VERSION 5.7 ;
BUSBITCHARS "[]" ;
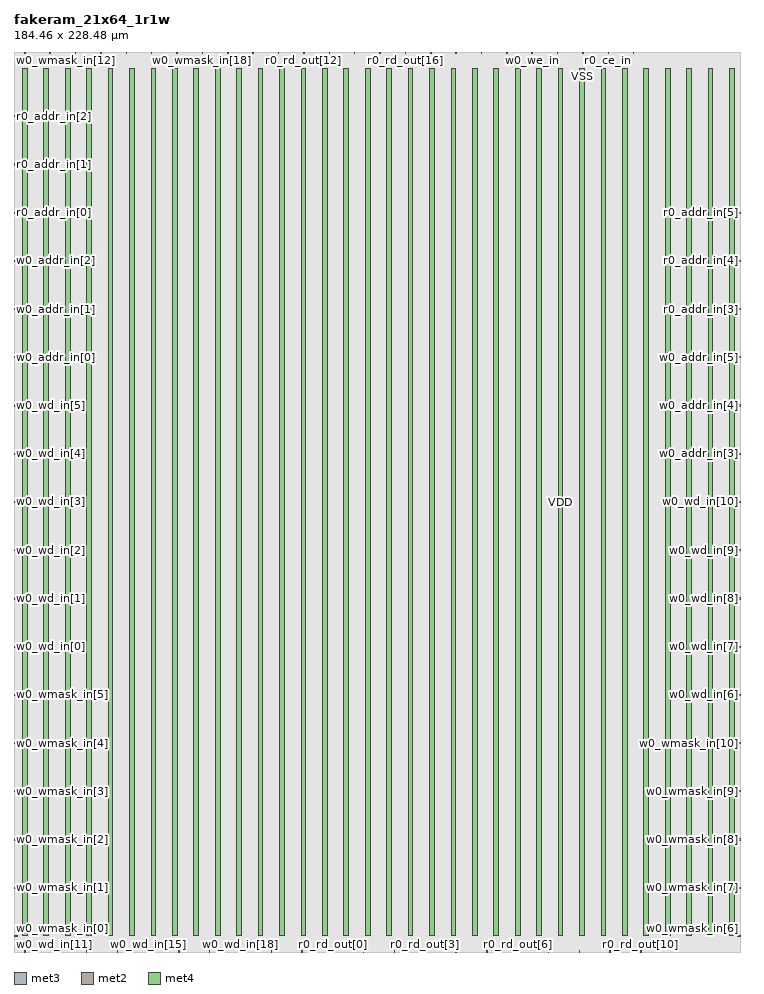
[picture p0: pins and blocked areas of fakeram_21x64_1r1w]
MACRO fakeram_21x64_1r1w
  FOREIGN fakeram_21x64_1r1w 0 0 ;
  SYMMETRY X Y R90 ;
  SIZE 184.460 BY 228.480 ;
  CLASS BLOCK ;
  PIN w0_wmask_in[0]
    DIRECTION INPUT ;
    USE SIGNAL ;
    SHAPE ABUTMENT ;
    PORT
      LAYER met3 ;
      RECT 0.000 3.930 0.900 4.230 ;
    END
  END w0_wmask_in[0]
  PIN w0_wmask_in[1]
    DIRECTION INPUT ;
    USE SIGNAL ;
    SHAPE ABUTMENT ;
    PORT
      LAYER met3 ;
      RECT 0.000 16.170 0.900 16.470 ;
    END
  END w0_wmask_in[1]
  PIN w0_wmask_in[2]
    DIRECTION INPUT ;
    USE SIGNAL ;
    SHAPE ABUTMENT ;
    PORT
      LAYER met3 ;
      RECT 0.000 28.410 0.900 28.710 ;
    END
  END w0_wmask_in[2]
  PIN w0_wmask_in[3]
    DIRECTION INPUT ;
    USE SIGNAL ;
    SHAPE ABUTMENT ;
    PORT
      LAYER met3 ;
      RECT 0.000 40.650 0.900 40.950 ;
    END
  END w0_wmask_in[3]
  PIN w0_wmask_in[4]
    DIRECTION INPUT ;
    USE SIGNAL ;
    SHAPE ABUTMENT ;
    PORT
      LAYER met3 ;
      RECT 0.000 52.890 0.900 53.190 ;
    END
  END w0_wmask_in[4]
  PIN w0_wmask_in[5]
    DIRECTION INPUT ;
    USE SIGNAL ;
    SHAPE ABUTMENT ;
    PORT
      LAYER met3 ;
      RECT 0.000 65.130 0.900 65.430 ;
    END
  END w0_wmask_in[5]
  PIN w0_wmask_in[6]
    DIRECTION INPUT ;
    USE SIGNAL ;
    SHAPE ABUTMENT ;
    PORT
      LAYER met3 ;
      RECT 183.560 3.930 184.460 4.230 ;
    END
  END w0_wmask_in[6]
  PIN w0_wmask_in[7]
    DIRECTION INPUT ;
    USE SIGNAL ;
    SHAPE ABUTMENT ;
    PORT
      LAYER met3 ;
      RECT 183.560 16.170 184.460 16.470 ;
    END
  END w0_wmask_in[7]
  PIN w0_wmask_in[8]
    DIRECTION INPUT ;
    USE SIGNAL ;
    SHAPE ABUTMENT ;
    PORT
      LAYER met3 ;
      RECT 183.560 28.410 184.460 28.710 ;
    END
  END w0_wmask_in[8]
  PIN w0_wmask_in[9]
    DIRECTION INPUT ;
    USE SIGNAL ;
    SHAPE ABUTMENT ;
    PORT
      LAYER met3 ;
      RECT 183.560 40.650 184.460 40.950 ;
    END
  END w0_wmask_in[9]
  PIN w0_wmask_in[10]
    DIRECTION INPUT ;
    USE SIGNAL ;
    SHAPE ABUTMENT ;
    PORT
      LAYER met3 ;
      RECT 183.560 52.890 184.460 53.190 ;
    END
  END w0_wmask_in[10]
  PIN w0_wmask_in[11]
    DIRECTION INPUT ;
    USE SIGNAL ;
    SHAPE ABUTMENT ;
    PORT
      LAYER met2 ;
      RECT 2.690 228.060 2.830 228.480 ;
    END
  END w0_wmask_in[11]
  PIN w0_wmask_in[12]
    DIRECTION INPUT ;
    USE SIGNAL ;
    SHAPE ABUTMENT ;
    PORT
      LAYER met2 ;
      RECT 9.130 228.060 9.270 228.480 ;
    END
  END w0_wmask_in[12]
  PIN w0_wmask_in[13]
    DIRECTION INPUT ;
    USE SIGNAL ;
    SHAPE ABUTMENT ;
    PORT
      LAYER met2 ;
      RECT 15.570 228.060 15.710 228.480 ;
    END
  END w0_wmask_in[13]
  PIN w0_wmask_in[14]
    DIRECTION INPUT ;
    USE SIGNAL ;
    SHAPE ABUTMENT ;
    PORT
      LAYER met2 ;
      RECT 22.010 228.060 22.150 228.480 ;
    END
  END w0_wmask_in[14]
  PIN w0_wmask_in[15]
    DIRECTION INPUT ;
    USE SIGNAL ;
    SHAPE ABUTMENT ;
    PORT
      LAYER met2 ;
      RECT 28.450 228.060 28.590 228.480 ;
    END
  END w0_wmask_in[15]
  PIN w0_wmask_in[16]
    DIRECTION INPUT ;
    USE SIGNAL ;
    SHAPE ABUTMENT ;
    PORT
      LAYER met2 ;
      RECT 34.890 228.060 35.030 228.480 ;
    END
  END w0_wmask_in[16]
  PIN w0_wmask_in[17]
    DIRECTION INPUT ;
    USE SIGNAL ;
    SHAPE ABUTMENT ;
    PORT
      LAYER met2 ;
      RECT 41.330 228.060 41.470 228.480 ;
    END
  END w0_wmask_in[17]
  PIN w0_wmask_in[18]
    DIRECTION INPUT ;
    USE SIGNAL ;
    SHAPE ABUTMENT ;
    PORT
      LAYER met2 ;
      RECT 47.770 228.060 47.910 228.480 ;
    END
  END w0_wmask_in[18]
  PIN w0_wmask_in[19]
    DIRECTION INPUT ;
    USE SIGNAL ;
    SHAPE ABUTMENT ;
    PORT
      LAYER met2 ;
      RECT 54.210 228.060 54.350 228.480 ;
    END
  END w0_wmask_in[19]
  PIN w0_wmask_in[20]
    DIRECTION INPUT ;
    USE SIGNAL ;
    SHAPE ABUTMENT ;
    PORT
      LAYER met2 ;
      RECT 60.650 228.060 60.790 228.480 ;
    END
  END w0_wmask_in[20]
  PIN w0_wd_in[0]
    DIRECTION INPUT ;
    USE SIGNAL ;
    SHAPE ABUTMENT ;
    PORT
      LAYER met3 ;
      RECT 0.000 77.370 0.900 77.670 ;
    END
  END w0_wd_in[0]
  PIN w0_wd_in[1]
    DIRECTION INPUT ;
    USE SIGNAL ;
    SHAPE ABUTMENT ;
    PORT
      LAYER met3 ;
      RECT 0.000 89.610 0.900 89.910 ;
    END
  END w0_wd_in[1]
  PIN w0_wd_in[2]
    DIRECTION INPUT ;
    USE SIGNAL ;
    SHAPE ABUTMENT ;
    PORT
      LAYER met3 ;
      RECT 0.000 101.850 0.900 102.150 ;
    END
  END w0_wd_in[2]
  PIN w0_wd_in[3]
    DIRECTION INPUT ;
    USE SIGNAL ;
    SHAPE ABUTMENT ;
    PORT
      LAYER met3 ;
      RECT 0.000 114.090 0.900 114.390 ;
    END
  END w0_wd_in[3]
  PIN w0_wd_in[4]
    DIRECTION INPUT ;
    USE SIGNAL ;
    SHAPE ABUTMENT ;
    PORT
      LAYER met3 ;
      RECT 0.000 126.330 0.900 126.630 ;
    END
  END w0_wd_in[4]
  PIN w0_wd_in[5]
    DIRECTION INPUT ;
    USE SIGNAL ;
    SHAPE ABUTMENT ;
    PORT
      LAYER met3 ;
      RECT 0.000 138.570 0.900 138.870 ;
    END
  END w0_wd_in[5]
  PIN w0_wd_in[6]
    DIRECTION INPUT ;
    USE SIGNAL ;
    SHAPE ABUTMENT ;
    PORT
      LAYER met3 ;
      RECT 183.560 65.130 184.460 65.430 ;
    END
  END w0_wd_in[6]
  PIN w0_wd_in[7]
    DIRECTION INPUT ;
    USE SIGNAL ;
    SHAPE ABUTMENT ;
    PORT
      LAYER met3 ;
      RECT 183.560 77.370 184.460 77.670 ;
    END
  END w0_wd_in[7]
  PIN w0_wd_in[8]
    DIRECTION INPUT ;
    USE SIGNAL ;
    SHAPE ABUTMENT ;
    PORT
      LAYER met3 ;
      RECT 183.560 89.610 184.460 89.910 ;
    END
  END w0_wd_in[8]
  PIN w0_wd_in[9]
    DIRECTION INPUT ;
    USE SIGNAL ;
    SHAPE ABUTMENT ;
    PORT
      LAYER met3 ;
      RECT 183.560 101.850 184.460 102.150 ;
    END
  END w0_wd_in[9]
  PIN w0_wd_in[10]
    DIRECTION INPUT ;
    USE SIGNAL ;
    SHAPE ABUTMENT ;
    PORT
      LAYER met3 ;
      RECT 183.560 114.090 184.460 114.390 ;
    END
  END w0_wd_in[10]
  PIN w0_wd_in[11]
    DIRECTION INPUT ;
    USE SIGNAL ;
    SHAPE ABUTMENT ;
    PORT
      LAYER met2 ;
      RECT 2.690 0.000 2.830 0.420 ;
    END
  END w0_wd_in[11]
  PIN w0_wd_in[12]
    DIRECTION INPUT ;
    USE SIGNAL ;
    SHAPE ABUTMENT ;
    PORT
      LAYER met2 ;
      RECT 10.510 0.000 10.650 0.420 ;
    END
  END w0_wd_in[12]
  PIN w0_wd_in[13]
    DIRECTION INPUT ;
    USE SIGNAL ;
    SHAPE ABUTMENT ;
    PORT
      LAYER met2 ;
      RECT 18.330 0.000 18.470 0.420 ;
    END
  END w0_wd_in[13]
  PIN w0_wd_in[14]
    DIRECTION INPUT ;
    USE SIGNAL ;
    SHAPE ABUTMENT ;
    PORT
      LAYER met2 ;
      RECT 26.150 0.000 26.290 0.420 ;
    END
  END w0_wd_in[14]
  PIN w0_wd_in[15]
    DIRECTION INPUT ;
    USE SIGNAL ;
    SHAPE ABUTMENT ;
    PORT
      LAYER met2 ;
      RECT 33.970 0.000 34.110 0.420 ;
    END
  END w0_wd_in[15]
  PIN w0_wd_in[16]
    DIRECTION INPUT ;
    USE SIGNAL ;
    SHAPE ABUTMENT ;
    PORT
      LAYER met2 ;
      RECT 41.790 0.000 41.930 0.420 ;
    END
  END w0_wd_in[16]
  PIN w0_wd_in[17]
    DIRECTION INPUT ;
    USE SIGNAL ;
    SHAPE ABUTMENT ;
    PORT
      LAYER met2 ;
      RECT 49.610 0.000 49.750 0.420 ;
    END
  END w0_wd_in[17]
  PIN w0_wd_in[18]
    DIRECTION INPUT ;
    USE SIGNAL ;
    SHAPE ABUTMENT ;
    PORT
      LAYER met2 ;
      RECT 57.430 0.000 57.570 0.420 ;
    END
  END w0_wd_in[18]
  PIN w0_wd_in[19]
    DIRECTION INPUT ;
    USE SIGNAL ;
    SHAPE ABUTMENT ;
    PORT
      LAYER met2 ;
      RECT 65.250 0.000 65.390 0.420 ;
    END
  END w0_wd_in[19]
  PIN w0_wd_in[20]
    DIRECTION INPUT ;
    USE SIGNAL ;
    SHAPE ABUTMENT ;
    PORT
      LAYER met2 ;
      RECT 73.070 0.000 73.210 0.420 ;
    END
  END w0_wd_in[20]
  PIN r0_rd_out[0]
    DIRECTION OUTPUT ;
    USE SIGNAL ;
    SHAPE ABUTMENT ;
    PORT
      LAYER met2 ;
      RECT 80.890 0.000 81.030 0.420 ;
    END
  END r0_rd_out[0]
  PIN r0_rd_out[1]
    DIRECTION OUTPUT ;
    USE SIGNAL ;
    SHAPE ABUTMENT ;
    PORT
      LAYER met2 ;
      RECT 88.710 0.000 88.850 0.420 ;
    END
  END r0_rd_out[1]
  PIN r0_rd_out[2]
    DIRECTION OUTPUT ;
    USE SIGNAL ;
    SHAPE ABUTMENT ;
    PORT
      LAYER met2 ;
      RECT 96.530 0.000 96.670 0.420 ;
    END
  END r0_rd_out[2]
  PIN r0_rd_out[3]
    DIRECTION OUTPUT ;
    USE SIGNAL ;
    SHAPE ABUTMENT ;
    PORT
      LAYER met2 ;
      RECT 104.350 0.000 104.490 0.420 ;
    END
  END r0_rd_out[3]
  PIN r0_rd_out[4]
    DIRECTION OUTPUT ;
    USE SIGNAL ;
    SHAPE ABUTMENT ;
    PORT
      LAYER met2 ;
      RECT 112.170 0.000 112.310 0.420 ;
    END
  END r0_rd_out[4]
  PIN r0_rd_out[5]
    DIRECTION OUTPUT ;
    USE SIGNAL ;
    SHAPE ABUTMENT ;
    PORT
      LAYER met2 ;
      RECT 119.990 0.000 120.130 0.420 ;
    END
  END r0_rd_out[5]
  PIN r0_rd_out[6]
    DIRECTION OUTPUT ;
    USE SIGNAL ;
    SHAPE ABUTMENT ;
    PORT
      LAYER met2 ;
      RECT 127.810 0.000 127.950 0.420 ;
    END
  END r0_rd_out[6]
  PIN r0_rd_out[7]
    DIRECTION OUTPUT ;
    USE SIGNAL ;
    SHAPE ABUTMENT ;
    PORT
      LAYER met2 ;
      RECT 135.630 0.000 135.770 0.420 ;
    END
  END r0_rd_out[7]
  PIN r0_rd_out[8]
    DIRECTION OUTPUT ;
    USE SIGNAL ;
    SHAPE ABUTMENT ;
    PORT
      LAYER met2 ;
      RECT 143.450 0.000 143.590 0.420 ;
    END
  END r0_rd_out[8]
  PIN r0_rd_out[9]
    DIRECTION OUTPUT ;
    USE SIGNAL ;
    SHAPE ABUTMENT ;
    PORT
      LAYER met2 ;
      RECT 151.270 0.000 151.410 0.420 ;
    END
  END r0_rd_out[9]
  PIN r0_rd_out[10]
    DIRECTION OUTPUT ;
    USE SIGNAL ;
    SHAPE ABUTMENT ;
    PORT
      LAYER met2 ;
      RECT 159.090 0.000 159.230 0.420 ;
    END
  END r0_rd_out[10]
  PIN r0_rd_out[11]
    DIRECTION OUTPUT ;
    USE SIGNAL ;
    SHAPE ABUTMENT ;
    PORT
      LAYER met2 ;
      RECT 67.090 228.060 67.230 228.480 ;
    END
  END r0_rd_out[11]
  PIN r0_rd_out[12]
    DIRECTION OUTPUT ;
    USE SIGNAL ;
    SHAPE ABUTMENT ;
    PORT
      LAYER met2 ;
      RECT 73.530 228.060 73.670 228.480 ;
    END
  END r0_rd_out[12]
  PIN r0_rd_out[13]
    DIRECTION OUTPUT ;
    USE SIGNAL ;
    SHAPE ABUTMENT ;
    PORT
      LAYER met2 ;
      RECT 79.970 228.060 80.110 228.480 ;
    END
  END r0_rd_out[13]
  PIN r0_rd_out[14]
    DIRECTION OUTPUT ;
    USE SIGNAL ;
    SHAPE ABUTMENT ;
    PORT
      LAYER met2 ;
      RECT 86.410 228.060 86.550 228.480 ;
    END
  END r0_rd_out[14]
  PIN r0_rd_out[15]
    DIRECTION OUTPUT ;
    USE SIGNAL ;
    SHAPE ABUTMENT ;
    PORT
      LAYER met2 ;
      RECT 92.850 228.060 92.990 228.480 ;
    END
  END r0_rd_out[15]
  PIN r0_rd_out[16]
    DIRECTION OUTPUT ;
    USE SIGNAL ;
    SHAPE ABUTMENT ;
    PORT
      LAYER met2 ;
      RECT 99.290 228.060 99.430 228.480 ;
    END
  END r0_rd_out[16]
  PIN r0_rd_out[17]
    DIRECTION OUTPUT ;
    USE SIGNAL ;
    SHAPE ABUTMENT ;
    PORT
      LAYER met2 ;
      RECT 105.730 228.060 105.870 228.480 ;
    END
  END r0_rd_out[17]
  PIN r0_rd_out[18]
    DIRECTION OUTPUT ;
    USE SIGNAL ;
    SHAPE ABUTMENT ;
    PORT
      LAYER met2 ;
      RECT 112.170 228.060 112.310 228.480 ;
    END
  END r0_rd_out[18]
  PIN r0_rd_out[19]
    DIRECTION OUTPUT ;
    USE SIGNAL ;
    SHAPE ABUTMENT ;
    PORT
      LAYER met2 ;
      RECT 118.610 228.060 118.750 228.480 ;
    END
  END r0_rd_out[19]
  PIN r0_rd_out[20]
    DIRECTION OUTPUT ;
    USE SIGNAL ;
    SHAPE ABUTMENT ;
    PORT
      LAYER met2 ;
      RECT 125.050 228.060 125.190 228.480 ;
    END
  END r0_rd_out[20]
  PIN w0_addr_in[0]
    DIRECTION INPUT ;
    USE SIGNAL ;
    SHAPE ABUTMENT ;
    PORT
      LAYER met3 ;
      RECT 0.000 150.810 0.900 151.110 ;
    END
  END w0_addr_in[0]
  PIN w0_addr_in[1]
    DIRECTION INPUT ;
    USE SIGNAL ;
    SHAPE ABUTMENT ;
    PORT
      LAYER met3 ;
      RECT 0.000 163.050 0.900 163.350 ;
    END
  END w0_addr_in[1]
  PIN w0_addr_in[2]
    DIRECTION INPUT ;
    USE SIGNAL ;
    SHAPE ABUTMENT ;
    PORT
      LAYER met3 ;
      RECT 0.000 175.290 0.900 175.590 ;
    END
  END w0_addr_in[2]
  PIN w0_addr_in[3]
    DIRECTION INPUT ;
    USE SIGNAL ;
    SHAPE ABUTMENT ;
    PORT
      LAYER met3 ;
      RECT 183.560 126.330 184.460 126.630 ;
    END
  END w0_addr_in[3]
  PIN w0_addr_in[4]
    DIRECTION INPUT ;
    USE SIGNAL ;
    SHAPE ABUTMENT ;
    PORT
      LAYER met3 ;
      RECT 183.560 138.570 184.460 138.870 ;
    END
  END w0_addr_in[4]
  PIN w0_addr_in[5]
    DIRECTION INPUT ;
    USE SIGNAL ;
    SHAPE ABUTMENT ;
    PORT
      LAYER met3 ;
      RECT 183.560 150.810 184.460 151.110 ;
    END
  END w0_addr_in[5]
  PIN r0_addr_in[0]
    DIRECTION INPUT ;
    USE SIGNAL ;
    SHAPE ABUTMENT ;
    PORT
      LAYER met3 ;
      RECT 0.000 187.530 0.900 187.830 ;
    END
  END r0_addr_in[0]
  PIN r0_addr_in[1]
    DIRECTION INPUT ;
    USE SIGNAL ;
    SHAPE ABUTMENT ;
    PORT
      LAYER met3 ;
      RECT 0.000 199.770 0.900 200.070 ;
    END
  END r0_addr_in[1]
  PIN r0_addr_in[2]
    DIRECTION INPUT ;
    USE SIGNAL ;
    SHAPE ABUTMENT ;
    PORT
      LAYER met3 ;
      RECT 0.000 212.010 0.900 212.310 ;
    END
  END r0_addr_in[2]
  PIN r0_addr_in[3]
    DIRECTION INPUT ;
    USE SIGNAL ;
    SHAPE ABUTMENT ;
    PORT
      LAYER met3 ;
      RECT 183.560 163.050 184.460 163.350 ;
    END
  END r0_addr_in[3]
  PIN r0_addr_in[4]
    DIRECTION INPUT ;
    USE SIGNAL ;
    SHAPE ABUTMENT ;
    PORT
      LAYER met3 ;
      RECT 183.560 175.290 184.460 175.590 ;
    END
  END r0_addr_in[4]
  PIN r0_addr_in[5]
    DIRECTION INPUT ;
    USE SIGNAL ;
    SHAPE ABUTMENT ;
    PORT
      LAYER met3 ;
      RECT 183.560 187.530 184.460 187.830 ;
    END
  END r0_addr_in[5]
  PIN w0_we_in
    DIRECTION INPUT ;
    USE SIGNAL ;
    SHAPE ABUTMENT ;
    PORT
      LAYER met2 ;
      RECT 131.490 228.060 131.630 228.480 ;
    END
  END w0_we_in
  PIN w0_ce_in
    DIRECTION INPUT ;
    USE SIGNAL ;
    SHAPE ABUTMENT ;
    PORT
      LAYER met2 ;
      RECT 137.930 228.060 138.070 228.480 ;
    END
  END w0_ce_in
  PIN w0_clk
    DIRECTION INPUT ;
    USE SIGNAL ;
    SHAPE ABUTMENT ;
    PORT
      LAYER met2 ;
      RECT 144.370 228.060 144.510 228.480 ;
    END
  END w0_clk
  PIN r0_ce_in
    DIRECTION INPUT ;
    USE SIGNAL ;
    SHAPE ABUTMENT ;
    PORT
      LAYER met2 ;
      RECT 150.810 228.060 150.950 228.480 ;
    END
  END r0_ce_in
  PIN r0_clk
    DIRECTION INPUT ;
    USE SIGNAL ;
    SHAPE ABUTMENT ;
    PORT
      LAYER met2 ;
      RECT 157.250 228.060 157.390 228.480 ;
    END
  END r0_clk
  PIN VSS
    DIRECTION INOUT ;
    USE GROUND ;
    PORT
      LAYER met4 ;
      RECT 2.160 4.080 3.360 224.400 ;
      RECT 13.040 4.080 14.240 224.400 ;
      RECT 23.920 4.080 25.120 224.400 ;
      RECT 34.800 4.080 36.000 224.400 ;
      RECT 45.680 4.080 46.880 224.400 ;
      RECT 56.560 4.080 57.760 224.400 ;
      RECT 67.440 4.080 68.640 224.400 ;
      RECT 78.320 4.080 79.520 224.400 ;
      RECT 89.200 4.080 90.400 224.400 ;
      RECT 100.080 4.080 101.280 224.400 ;
      RECT 110.960 4.080 112.160 224.400 ;
      RECT 121.840 4.080 123.040 224.400 ;
      RECT 132.720 4.080 133.920 224.400 ;
      RECT 143.600 4.080 144.800 224.400 ;
      RECT 154.480 4.080 155.680 224.400 ;
      RECT 165.360 4.080 166.560 224.400 ;
      RECT 176.240 4.080 177.440 224.400 ;
    END
  END VSS
  PIN VDD
    DIRECTION INOUT ;
    USE POWER ;
    PORT
      LAYER met4 ;
      RECT 7.600 4.080 8.800 224.400 ;
      RECT 18.480 4.080 19.680 224.400 ;
      RECT 29.360 4.080 30.560 224.400 ;
      RECT 40.240 4.080 41.440 224.400 ;
      RECT 51.120 4.080 52.320 224.400 ;
      RECT 62.000 4.080 63.200 224.400 ;
      RECT 72.880 4.080 74.080 224.400 ;
      RECT 83.760 4.080 84.960 224.400 ;
      RECT 94.640 4.080 95.840 224.400 ;
      RECT 105.520 4.080 106.720 224.400 ;
      RECT 116.400 4.080 117.600 224.400 ;
      RECT 127.280 4.080 128.480 224.400 ;
      RECT 138.160 4.080 139.360 224.400 ;
      RECT 149.040 4.080 150.240 224.400 ;
      RECT 159.920 4.080 161.120 224.400 ;
      RECT 170.800 4.080 172.000 224.400 ;
      RECT 181.680 4.080 182.880 224.400 ;
    END
  END VDD
  OBS
    LAYER met1 ;
    RECT 0 0 184.460 228.480 ;
    LAYER met2 ;
    RECT 0 0 184.460 228.480 ;
    LAYER met3 ;
    RECT 0 0 184.460 228.480 ;
    LAYER met4 ;
    RECT 0 0 184.460 228.480 ;
  END
END fakeram_21x64_1r1w

END LIBRARY
